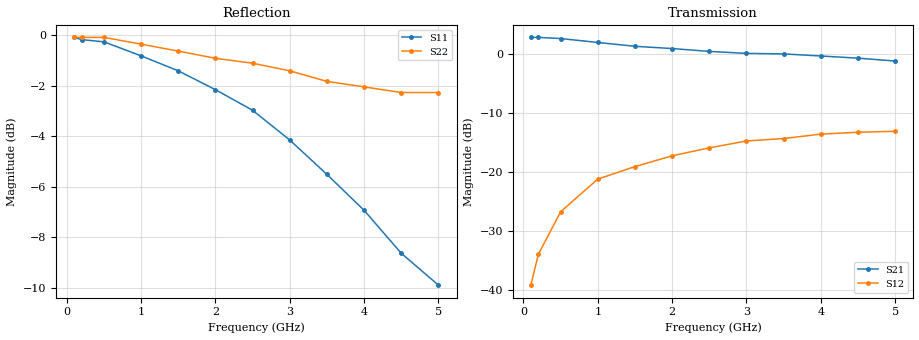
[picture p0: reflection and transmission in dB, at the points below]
!AT-60111
!S-PARAMETERS at Vce=3V  Ic=0.4mA.  LAST UPDATED 07-21-92
# ghz s ma r 50
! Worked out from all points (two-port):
!   12 points, 100 MHz to 5 GHz, reference 50 ohm
!   highest |S21| = 2.80 dB at 200 MHz (marker M1); lowest = -1.2 dB at 5 GHz (marker M2)
!   |S21| within 3 dB of the highest: start of sweep to 3.785 GHz
!   lowest |S11| = -9.9 dB at 5 GHz (marker M3), VSWR 1.94, Z = 36.3 - j25.3 ohm
!   |S11| at or under -10 dB: nowhere
!   |S22| runs from -2.3 to -0.1 dB; largest |S21 - S12| = 1.4
!   S11 on the Smith chart (normalised r, x): 100 MHz: 7, -37; 1 GHz: 0.78, -3.86; 1.5 GHz: 0.72, -2.73; 3 GHz: 0.83, -1.43; 4 GHz: 0.77, -0.86; 5 GHz: 0.73, -0.51
0.1  0.99 -3.0  1.38 176.0  0.011 85.0  0.99 -3.0
0.2  0.98 -6.0  1.38 171.0  0.02 90.0  0.99 -5.0
0.5  0.97 -15.0  1.35 159.0  0.046 75.0  0.99 -12.0
1  0.91 -28.0  1.25 140.0  0.087 64.0  0.96 -22.0
1.5  0.85 -38.0  1.16 124.0  0.111 58.0  0.93 -29.0
2  0.78 -45.0  1.11 111.0  0.137 52.0  0.9 -35.0
2.5  0.71 -51.0  1.05 101.0  0.16 48.0  0.88 -38.0
3  0.62 -59.0  1.01 88.0  0.183 41.0  0.85 -44.0
3.5  0.53 -68.0  1 76.0  0.192 37.0  0.81 -51.0
4  0.45 -79.0  0.96 64.0  0.209 30.0  0.79 -57.0
4.5  0.37 -90.0  0.92 52.0  0.217 25.0  0.77 -64.0
5  0.32 -102.0  0.87 42.0  0.221 20.0  0.77 -70.0
